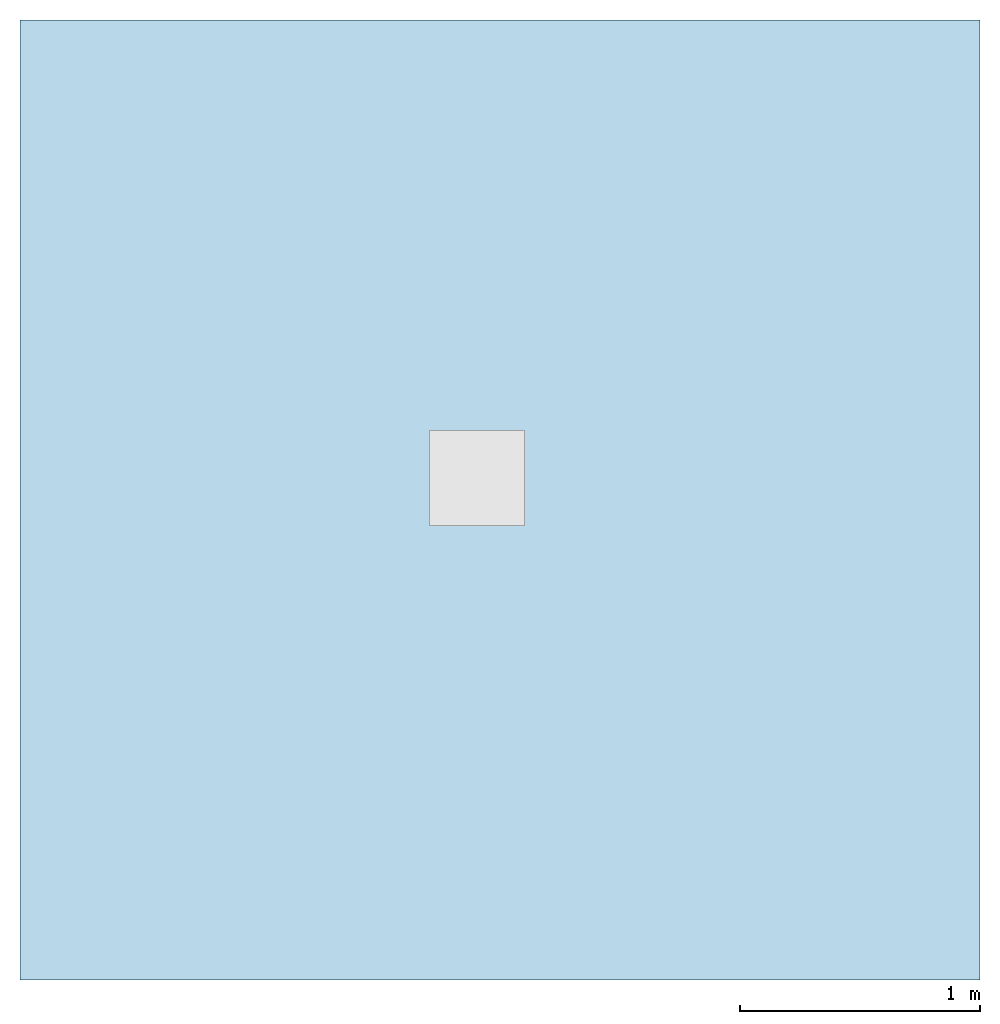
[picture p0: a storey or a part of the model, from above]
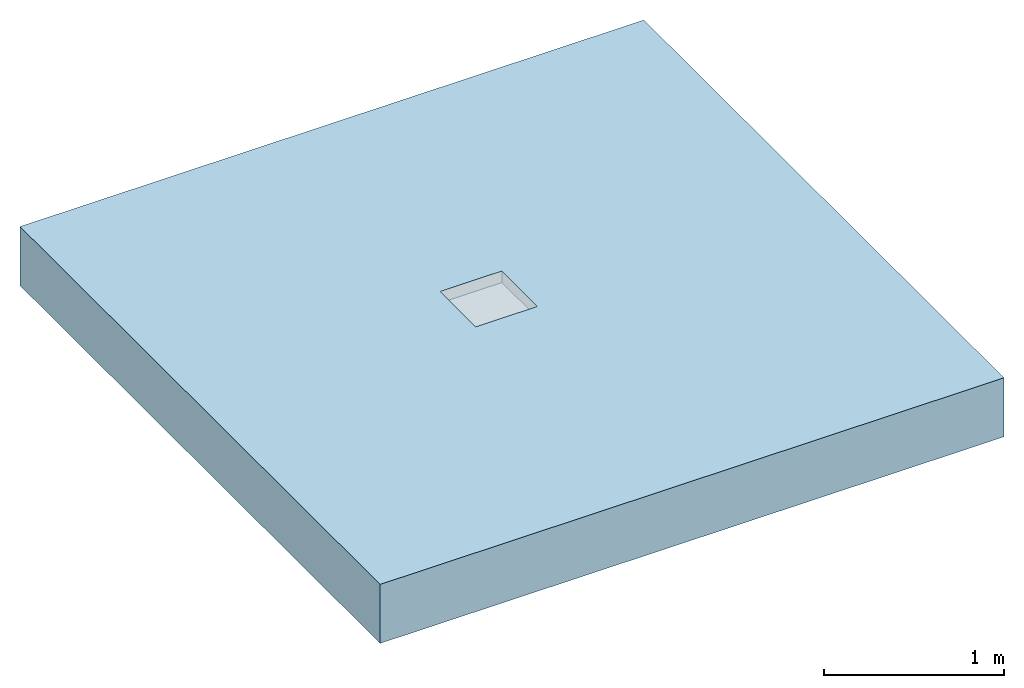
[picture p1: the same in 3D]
Properties of the parts of a building model (IFC2X3)

# File
Description: ViewDefinition [CoordinationView]
File name: Project Number
Time: 2014-06-06T10:57:18
Written by: The EXPRESS Data Manager Version 5.01.0100.02.64mod : 6 Jun 2012
Made in: 20130308_1515(x64) - Exporter 2014.0.2013.0308 - Default UI
Comment: STEP Physical File produced by: The EXPRESS Data Manager Version 5.01.0100.02.64mod : 6 Jun 2012 * Module: EDMstepFileFactory/EDMstandAlone * Creation date: Fri Jun 06 10:57:18 2014 * Host: IN-BLR-PC-0010 * Database: C:\Users\palleri\AppData\Local\Temp\{BAEFB53F-186B-4729-BCE4-73532F2C6562}\ifc * Database version: 5507 * Database creation date: Fri Jun 06 10:57:18 2014 * Schema: IFC2X3 * Model: DataRepository.ifc * Model creation date: Fri Jun 06 10:57:18 2014 * Header model: DataRepository.ifc_HeaderModel * Header model creation date: Fri Jun 06 10:57:18 2014 * EDMuser: sdai-user * EDMgroup: sdai-group * License ID and type: 5605 : Permanent license. Expiry date: * EDMstepFileFactory options: 020000

# IfcProject, Project Number
LongName: Project Name; Phase: Project Status

# IfcSite, Default
RefLatitude: 42, 21, 30, 344238; RefLongitude: -71, -3, -35, -194702; RefElevation: 0 mm

# IfcBuilding
Pset_BuildingCommon - NumberOfStoreys: 1
Other - Project Status: Project Status; Project Number: Project Number; Project Issue Date: Issue Date; Project Name: Project Name; Client Name: Owner; Project Address: ## Street City, State Zip

# IfcBuildingStorey, Level 1
LongName: Level 1; Elevation: 0 mm
Constraints - Elevation Base: Project Base Point; Elevation: 0 mm
Graphics - Symbol at End 1 Default: no; Symbol at End 2 Default: yes; Line Pattern: Center; Line Weight: 1; Symbol: M_Level Head - Circle: M_Level Head - Circle; Color: 0
Dimensions - Computation Height: 0 mm
Identity Data - Name: Level 1; Structural: no; Building Story: yes

# IfcFlowTerminal: 38150 - Access Frame - Fixed Height - Invert Depth 50mm, ACO Freedeck Access Frame & Drain Duct (Accessories part 1) V1.27 - GS:38150 - Access Frame - Fixed Height - Invert Depth 50mm:276243
In: Level 1
Material: Galvanized Steel
Materials and Finishes - Material: Galvanized Steel
Identity Data - Mark: 14; Address: ACO Business Centre, Caxton Road, Bedford, MK41 0LF; Watermark2: This file is water marked and users are prohibited to reproduce, adapt, distribute this information; E-mail Technical: abdtechnical@aco.co.uk; Watermarked By: www.acobd.com; Manufacturer: ACO Building Drainage; Watermarked With: BIM Manager Premium Suite; Watermark1: This file is the property of ACO Technologies PLC; Fax: +44 (0)1462 851490; E-mail Sales: abdcommercial@aco.co.uk; Website: www.acobd.com; Telephone: +44 (0)1462 816666
Dimensions - Top Void Height End: -30 mm; Base Height: 3000 mm; Drainage Duct – Level below FFL: 30 mm; Height for Adjustable Access Frame: 105 mm; Top Void Height Start: -80 mm; Access Frame Extension Position Height: 0 mm; Total Height: 134 mm; Grating Start: 0 mm; Grating End: -20 mm; Drain Duct End: -100 mm
Phasing - Phase Created: New Construction
Construction - 36754_Access Grating_Mesh Grating_Galvanized Steel: yes; 38685_Access Frame Extension_Galvanized Steel_Invert Depth 50mm: yes; 38687_Access Frame Extension_Galvanized Steel_Invert Depth 75mm: no
Other - Adjustable Access Frame Position Height: 105 mm; Fixed Access Frame Position Height: 80 mm; Extension Removal Void: -2 mm; Access Frame Extension_Invert Depth 75mm: no; Drain Duct Vertical Height: 5000 mm; Access Frame Extension: yes; Access Frame Extension Height: 50 mm; Access Frame Extension_Invert Depth 50mm: yes; Top void Size: 400 mm; Grating: yes; Drain Duct: no; Access Frame Fixed Height: yes; Access Frame Adjustable Height: no
Constraints - Moves With Nearby Elements: no; Level: Level: Level 1
Pset_ManufacturerTypeInformation - Manufacturer: ACO Building Drainage
General - Channel Colour: Galvanised; Channel Recycled Material Content: 25 - 30 %; Weight (Kg): 5.7kg; Maintenance Guidelines: X:\Electronic Literature\ABD Electronic Literature\Roof and Balcony Drainage\ACO Freedeck Brochure.pdf; Channel Recyclable: Fully recyclable; Load Class: A15; Installation Guidelines: X:\Electronic Literature\ABD Electronic Literature\Roof and Balcony Drainage\ACO Freedeck Brochure.pdf; Channel Material: Hot Dipped Galvanised Steel; Price: POA - contact ACO; Product Description: ACO Freedeck Access Frame - Adjustable; NBS Specification: NBS Section R10 Gravity Rainwater Drainage Systems, Subsection 365; Product Code: 38150; Product Range: ACO Freedeck; Product Standard: BS EN 1433:2002, CE marked; Product Type: Linear Deck Drainage System; Dimensions (LxWxH): 400 x 400 x 50
Model Properties - Access Frame Extension Product Code 38688: N/A; Access Frame Extension Product Code 38687: Load Class A15 - Access Frame Extension - Galvanized Steel - Invert Depth 75mm - 1.9kg; Access Grating Product Code 36760: N/A; Access Frame Extension Product Code 38686: N/A; Access Grating Product Code 36754: Load Class A15 - Mesh Grating - 14mm x 30mm Mesh - Galvanized Steel - 3.5kg; Access Frame Extension Product Code 38685: Load Class A15 - Access Frame Extension - Galvanized Steel - Invert Depth 50mm - 1.3kg

# IfcOpeningElement: Opening (3)
In: Level 1
Constraints - Height Offset From Level: 0 mm; Room Bounding: yes; Level: Level: Level 1; Related to Mass: no
Dimensions - Volume: 6.38732 m3; Thickness: 400 mm; Area: 16 m2; Perimeter: 16000 mm
Phasing - Phase Created: New Construction
Structural - Structural: no; Enable Analytical Model: no
Construction - Default Thickness: 400 mm; Function: Interior
Analytical Properties - Thermal Resistance (R): 0.382409; Roughness: 1; Heat Transfer Coefficient (U): 2.615; Absorptance: 0.1; Thermal mass: 604440
Graphics - Coarse Scale Fill Color: 0
Materials and Finishes - Structural Material: Concrete, Broom Finish

# IfcSlab: Floor:Generic Floor - 400mm, Floor:Generic Floor - 400mm:193825
In: Level 1
PredefinedType: FLOOR; Material: Concrete, Broom Finish 400 mm
Constraints - Height Offset From Level: 0 mm; Room Bounding: yes; Level: Level: Level 1; Related to Mass: no
Dimensions - Volume: 6.38732 m3; Thickness: 400 mm; Area: 16 m2; Perimeter: 16000 mm
Phasing - Phase Created: New Construction
Structural - Structural: no; Enable Analytical Model: no
Pset_SlabCommon - Reference: Generic Floor - 400mm; IsExternal: no; LoadBearing: yes; ThermalTransmittance: 2.615 kg/K/s3
Construction - Default Thickness: 400 mm; Function: Interior
Analytical Properties - Thermal Resistance (R): 0.382409; Roughness: 1; Heat Transfer Coefficient (U): 2.615; Absorptance: 0.1; Thermal mass: 604440
Graphics - Coarse Scale Fill Color: 0
Materials and Finishes - Structural Material: Concrete, Broom Finish
